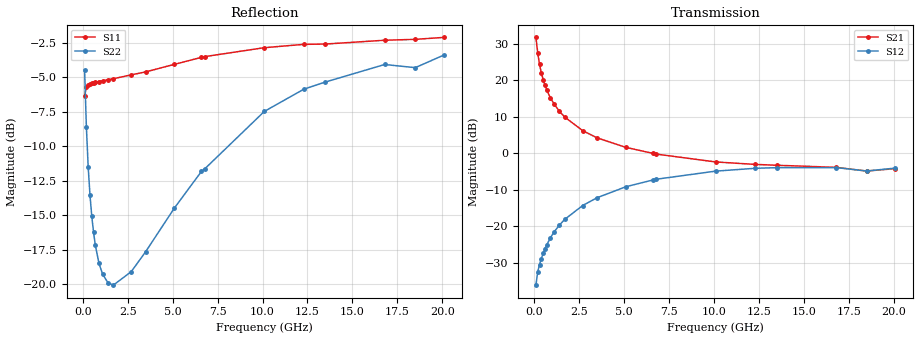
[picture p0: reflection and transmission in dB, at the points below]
!  Infineon Technologies AG
! BFR380L3 , PF131585-7, No.6, Th 09.10.01, soldered on pcb-board, measured with PP GSG850
!  Vce=4.0 V,  Ic=75.0 mA
! Common Emitter S-Parameters:  15. November 2001
#  GHz  S  MA  R  50
! f  S11  S21  S12  S22
! GHz  Mag  Ang  Mag  Ang  Mag  Ang  Mag  Ang
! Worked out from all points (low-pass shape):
!   201 points, 100 MHz to 20.1 GHz, reference 50 ohm
!   highest |S21| = 31.77 dB at 100 MHz (marker M1); lowest = -4.9 dB at 18.5 GHz (marker M2)
!   |S21| within 3 dB of the highest: start of sweep to 169.9 MHz
!   lowest |S11| = -6.4 dB at 100 MHz (marker M3), VSWR 2.84, Z = 26.1 - j31.4 ohm
!   |S11| at or under -10 dB: nowhere
!   |S22| runs from -20.1 to -3.4 dB; largest |S21 - S12| = 39
!   S11 on the Smith chart (normalised r, x): 100 MHz: 0.52, -0.63; 400 MHz: 0.31, -0.14; 2.7 GHz: 0.29, +0.28; 6.6 GHz: 0.33, +0.76; 12.3 GHz: 0.51, +1.49; 20.1 GHz: 1.04, +2.57
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0.1  0.4797 -104.8  38.76 130.6  0.0155 61.7  0.5957 -47.5
0.2  0.5186 -139.2  23.64 111.2  0.02379 57.2  0.3706 -64.4
0.3  0.5251 -154.5  16.55 102.4  0.02961 59.9  0.2663 -71.4
0.4  0.5319 -162.6  12.66 96.8  0.03586 63.1  0.2101 -75.3
0.5  0.5351 -168.6  10.22 92.9  0.04222 65.7  0.1762 -78.0
0.6  0.5372 -173.0  8.569 89.8  0.04882 67.0  0.1539 -80.1
0.7  0.539 -176.6  7.383 87.1  0.05517 68.3  0.1381 -82.1
0.9  0.5418 177.8  5.777 82.5  0.06883 69.6  0.1189 -85.4
1.1  0.5453 173.2  4.758 78.5  0.0825 70.1  0.1087 -89.5
1.4  0.5501 167.2  3.768 73.1  0.1029 69.8  0.1012 -95.2
1.7  0.5544 161.8  3.128 68.2  0.1235 69.0  0.09916 -101.8
2.7  0.5728 146.4  2.041 53.3  0.1915 64.0  0.111 -124.0
3.5  0.587 135.5  1.624 42.8  0.2448 59.0  0.1311 -138.4
5.1  0.6252 116.8  1.202 25.0  0.3462 47.7  0.1887 -167.0
6.6  0.6626 101.6  0.995 11.9  0.4288 37.2  0.2558 169.9
6.8  0.667 99.6  0.9718 10.3  0.4394 35.6  0.262 167.2
10.1  0.7183 75.0  0.7583 -8.8  0.5674 12.8  0.4221 130.8
12.3  0.7386 63.4  0.7017 -17.9  0.6205 -1.5  0.5082 110.0
13.5  0.7405 57.7  0.6828 -23.1  0.633 -8.8  0.5395 100.8
16.8  0.7644 46.1  0.6396 -33.4  0.6345 -25.2  0.6244 78.4
18.5  0.7701 44.3  0.5691 -40.6  0.5698 -33.5  0.6081 72.6
20.1  0.7828 37.6  0.6141 -43.9  0.6243 -38.9  0.676 61.5
